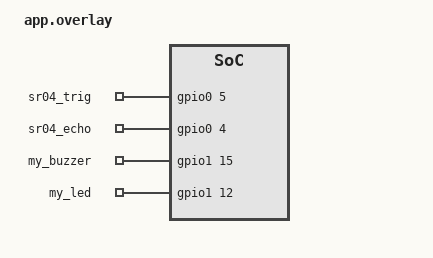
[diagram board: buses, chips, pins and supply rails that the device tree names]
/ {
    aliases {
        sr04-trig = &sr04_trig;
        sr04-echo = &sr04_echo;
        my-buzzer = &my_buzzer;
        my-led = &my_led;
    };

    keypad_pins {
        compatible = "gpio-keys";
        sr04_trig: sr04_trig {
            gpios = <&gpio0 5 (GPIO_ACTIVE_HIGH | GPIO_PULL_UP)>;
        };
        sr04_echo: sr04_echo {
            gpios = <&gpio0 4 (GPIO_ACTIVE_HIGH | GPIO_PULL_UP)>;
        };
        my_buzzer: my_buzzer {
            gpios = <&gpio1 15 (GPIO_ACTIVE_HIGH)>;
        };
        my_led: my_led {
            gpios = <&gpio1 12 (GPIO_ACTIVE_HIGH)>;
        };
    };
};
